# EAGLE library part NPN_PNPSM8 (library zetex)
Dual NPN TRANSISTOR

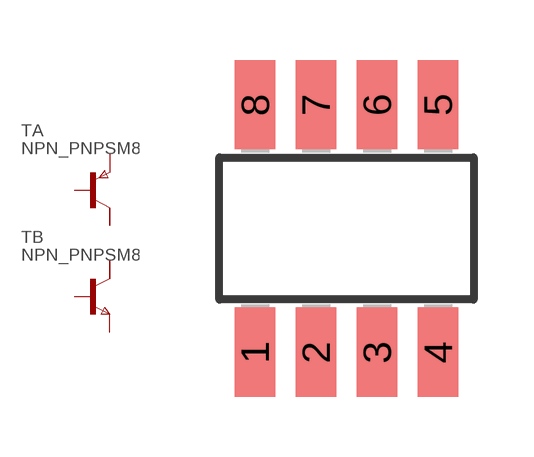
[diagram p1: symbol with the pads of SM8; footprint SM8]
Designator prefix T; gates A=PNP2C B=NPN2C

## NPN_PNPSM8  [SM8]
1  A:E  pas
2  A:B  pas
3  B:C1  pas
4  B:C2  pas
5  B:B  pas
6  B:E  pas
7  A:C  pas
8  A:C1  pas

## Footprint SM8 (pad centres in mm)
SM8 Package
smd 1.016 x 2.235: 1 -2.286,-3.099; 2 -0.762,-3.099; 3 0.762,-3.099; 4 2.286,-3.099; 5 2.286,3.099; 6 0.762,3.099; 7 -0.762,3.099; 8 -2.286,3.099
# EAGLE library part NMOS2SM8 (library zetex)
Dual MOS FET

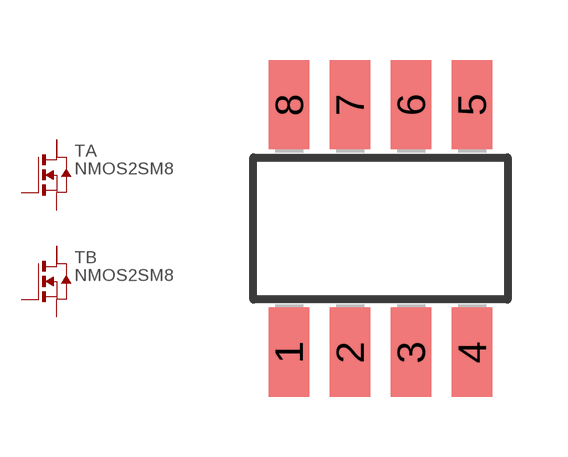
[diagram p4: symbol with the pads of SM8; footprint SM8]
Designator prefix T; gates A=N_MOS2D B=N_MOS2D

## NMOS2SM8  [SM8]
1  A:S  pas
2  A:G  pas
3  B:D  pas
4  B:D2  pas
5  B:G  pas
6  B:S  pas
7  A:D2  pas
8  A:D  pas

## Footprint SM8 (pad centres in mm)
SM8 Package
smd 1.016 x 2.235: 1 -2.286,-3.099; 2 -0.762,-3.099; 3 0.762,-3.099; 4 2.286,-3.099; 5 2.286,3.099; 6 0.762,3.099; 7 -0.762,3.099; 8 -2.286,3.099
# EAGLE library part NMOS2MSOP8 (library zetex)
Dual MOS FET

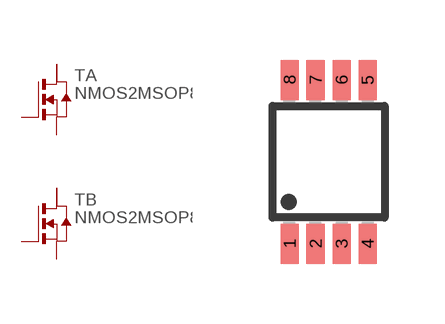
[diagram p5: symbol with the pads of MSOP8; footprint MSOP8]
Designator prefix T; gates A=N_MOS2D B=N_MOS2D

## NMOS2MSOP8  [MSOP8]
1  A:S  pas
2  A:G  pas
3  B:S  pas
4  B:G  pas
5  B:D2  pas
6  B:D  pas
7  A:D2  pas
8  A:D  pas

## Footprint MSOP8 (pad centres in mm)
Micro Small Outline Package
smd 0.45 x 1: 1 -0.975,-2.05; 2 -0.325,-2.05; 3 0.325,-2.05; 4 0.975,-2.05; 5 0.975,2.05; 6 0.325,2.05; 7 -0.325,2.05; 8 -0.975,2.05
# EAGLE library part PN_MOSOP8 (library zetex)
Dual MOS FET

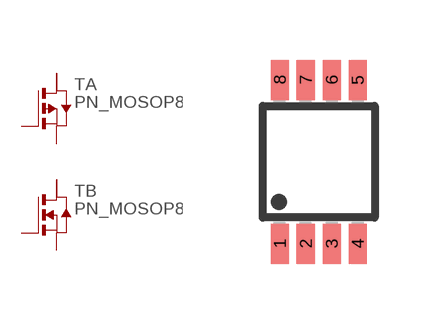
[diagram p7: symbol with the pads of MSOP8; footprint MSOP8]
Designator prefix T; gates A=P_MOS2D B=N_MOS2D

## PN_MOSOP8  [MSOP8]
1  A:S  pas
2  A:G  pas
3  B:D  pas
4  B:D2  pas
5  B:G  pas
6  B:S  pas
7  A:D  pas
8  A:D2  pas

## Footprint MSOP8 (pad centres in mm)
Micro Small Outline Package
smd 0.45 x 1: 1 -0.975,-2.05; 2 -0.325,-2.05; 3 0.325,-2.05; 4 0.975,-2.05; 5 0.975,2.05; 6 0.325,2.05; 7 -0.325,2.05; 8 -0.975,2.05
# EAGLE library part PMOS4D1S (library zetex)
MOS FET

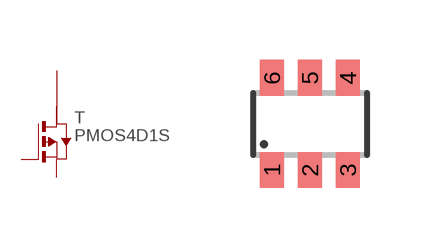
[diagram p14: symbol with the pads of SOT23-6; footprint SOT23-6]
Designator prefix T

## PMOS4D1S  [SOT23-6]
1  D  pas
2  D1  pas
3  G  pas
4  S  pas
5  D2  pas
6  D3  pas

## Footprint SOT23-6 (pad centres in mm)
Small Outline Transistor 6 lead
smd 0.6 x 0.9: 1 -0.95,-1.15; 2 0,-1.15; 3 0.95,-1.15; 4 0.95,1.15; 5 0,1.15; 6 -0.95,1.15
